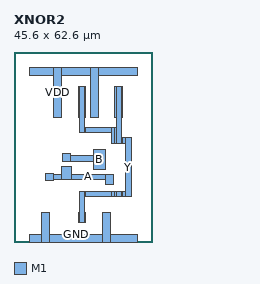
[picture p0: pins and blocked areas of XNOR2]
MACRO XNOR2
  CLASS CORE ;
  ORIGIN 0 0 ;
  SIZE 45.600 BY 62.600 ;
  SYMMETRY X Y ;
  SITE TR1um_site ;
  PIN Y
    DIRECTION OUTPUT ;
    USE SIGNAL ;
    PORT
      LAYER M1 ;
        RECT 21.100 6.400 21.500 9.800 ;
      LAYER M1 ;
        RECT 21.100 41.000 21.500 51.200 ;
      LAYER M1 ;
        RECT 21.500 6.400 23.300 16.800 ;
      LAYER M1 ;
        RECT 21.500 36.000 23.300 51.200 ;
      LAYER M1 ;
        RECT 23.300 6.400 23.700 9.800 ;
      LAYER M1 ;
        RECT 23.300 15.000 23.700 16.800 ;
      LAYER M1 ;
        RECT 23.300 36.000 23.700 37.800 ;
      LAYER M1 ;
        RECT 23.300 41.000 23.700 51.200 ;
      LAYER M1 ;
        RECT 23.700 15.000 32.100 16.800 ;
      LAYER M1 ;
        RECT 23.700 36.000 32.100 37.800 ;
      LAYER M1 ;
        RECT 32.100 15.000 33.100 16.800 ;
      LAYER M1 ;
        RECT 32.100 32.600 33.100 37.800 ;
      LAYER M1 ;
        RECT 33.100 15.000 33.700 16.800 ;
      LAYER M1 ;
        RECT 33.100 32.600 33.700 37.800 ;
      LAYER M1 ;
        RECT 33.100 41.000 33.700 51.200 ;
      LAYER M1 ;
        RECT 33.700 15.000 35.500 16.800 ;
      LAYER M1 ;
        RECT 33.700 32.600 35.500 51.200 ;
      LAYER M1 ;
        RECT 35.500 15.000 35.700 16.800 ;
      LAYER M1 ;
        RECT 35.500 32.600 35.700 34.400 ;
      LAYER M1 ;
        RECT 35.500 41.000 35.700 51.200 ;
      LAYER M1 ;
        RECT 35.700 15.000 36.800 16.800 ;
      LAYER M1 ;
        RECT 35.700 32.600 36.800 34.400 ;
      LAYER M1 ;
        RECT 36.800 15.000 38.600 34.400 ;
    END
  END Y
  PIN A
    DIRECTION INPUT ;
    USE SIGNAL ;
    PORT
      LAYER M1 ;
        RECT 10.300 20.100 12.900 22.700 ;
      LAYER M1 ;
        RECT 12.900 20.600 15.600 22.400 ;
      LAYER M1 ;
        RECT 15.600 20.600 19.000 25.000 ;
      LAYER M1 ;
        RECT 19.000 20.600 30.300 22.400 ;
      LAYER M1 ;
        RECT 30.300 19.000 32.900 22.400 ;
    END
  END A
  PIN B
    DIRECTION INPUT ;
    USE SIGNAL ;
    PORT
      LAYER M1 ;
        RECT 15.900 26.600 18.500 29.200 ;
      LAYER M1 ;
        RECT 18.500 26.600 26.300 28.400 ;
      LAYER M1 ;
        RECT 26.300 23.800 30.000 30.500 ;
    END
  END B
  PIN VDD
    DIRECTION INOUT ;
    USE POWER ;
    PORT
      LAYER M1 ;
        RECT 5.000 55.000 13.100 57.600 ;
      LAYER M1 ;
        RECT 13.100 41.000 15.700 57.600 ;
      LAYER M1 ;
        RECT 15.700 55.000 25.100 57.600 ;
      LAYER M1 ;
        RECT 25.100 41.000 27.700 57.600 ;
      LAYER M1 ;
        RECT 27.700 55.000 40.600 57.600 ;
    END
  END VDD
  PIN GND
    DIRECTION INOUT ;
    USE GROUND ;
    PORT
      LAYER M1 ;
        RECT 5.000 0.000 9.100 2.600 ;
      LAYER M1 ;
        RECT 9.100 0.000 11.700 9.800 ;
      LAYER M1 ;
        RECT 11.700 0.000 29.100 2.600 ;
      LAYER M1 ;
        RECT 29.100 0.000 31.700 9.800 ;
      LAYER M1 ;
        RECT 31.700 0.000 40.600 2.600 ;
    END
  END GND
END XNOR2
